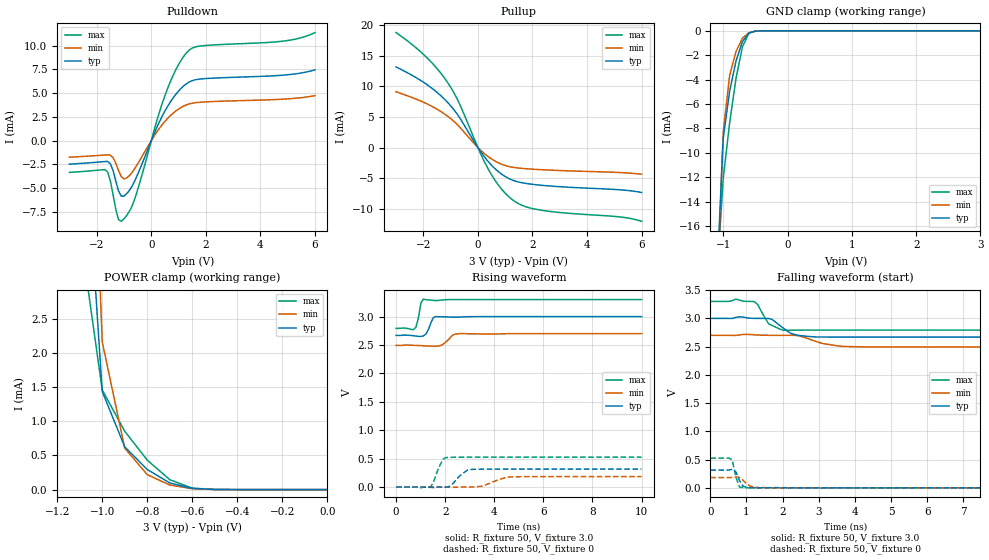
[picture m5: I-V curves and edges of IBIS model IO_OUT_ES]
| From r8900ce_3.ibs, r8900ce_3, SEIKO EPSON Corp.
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[Model]   IO_OUT_ES
Model_type 3-state
Enable Active-High
Polarity Non-Inverting
Vmeas=1.50
C_comp   2.5p   2p   3p
[Temperature Range] 25   85   -40
[Voltage Range]   3.0   2.7   3.3
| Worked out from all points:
|   slope of the pulldown table from 0 to 0.45 V, typ, clamps not added: 157 ohm
|   slope of the pullup table from 0 to 0.45 V, typ, clamps not added: 170 ohm
|   GND clamp passes 1 mA (typ) near -0.71 V on its own axis
|   POWER clamp passes 1 mA (typ) near -0.95 V on its own axis
|   falling waveform, R_fixture 50, V_fixture 3.0: 20-80 % time 430ps typ, 688ps min, 291ps max; typ from 3 V to 2.67 V
|   falling waveform, R_fixture 50, V_fixture 0: 20-80 % time 145ps typ, 215ps min, 125ps max; typ from 0.315 V to 0 V
|   rising waveform, R_fixture 50, V_fixture 3.0: 20-80 % time 196ps typ, 303ps min, 136ps max; typ from 2.67 V to 3 V
|   rising waveform, R_fixture 50, V_fixture 0: 20-80 % time 436ps typ, 664ps min, 290ps max; typ from 0 V to 0.315 V
[Pullup]
-3V       13.15mA    9.1mA      18.76mA
-2V       10.67mA    7.402mA    15.22mA
-1.2V     7.774mA    5.394mA    11.17mA
-700mV    5.069mA    3.488mA    7.383mA
100mV     -670.8uA   -442.9uA   -1.015mA
400mV     -2.405mA   -1.562mA   -3.683mA
800mV     -4.114mA   -2.598mA   -6.416mA
1.3V      -5.375mA   -3.246mA   -8.638mA
1.7V      -5.817mA   -3.436mA   -9.577mA
2.3V      -6.149mA   -3.611mA   -10.21mA
5.2V      -6.899mA   -4.083mA   -11.33mA
6V        -7.339mA   -4.363mA   -12.04mA
[Pulldown]
-3V       -2.479mA   -1.747mA   -3.344mA
-1.6V     -2.194mA   -1.497mA   -3.304mA
-1.4V     -3.175mA   -1.806mA   -5.728mA
-1.2V     -5.321mA   -3.18mA    -8.323mA
-1.1V     -5.852mA   -3.796mA   -8.495mA
-900mV    -5.578mA   -3.932mA   -7.863mA
-600mV    -4.197mA   -2.907mA   -6.073mA
600mV     3.627mA    2.353mA    5.517mA
1.3V      6.014mA    3.781mA    9.282mA
1.8V      6.487mA    4.045mA    9.961mA
4.8V      6.886mA    4.362mA    10.47mA
6V        7.452mA    4.738mA    11.38mA
[GND Clamp]
-3V       -430mA     -359.3mA   -539.8mA
-1.1V     -20.64mA   -22.12mA   -20.39mA
-1V       -8.831mA   -8.329mA   -12.11mA
-900mV    -4.941mA   -3.657mA   -7.543mA
-800mV    -2.459mA   -1.675mA   -3.865mA
-700mV    -864uA     -604.2uA   -1.29mA
-600mV    -179.4uA   -151uA     -195.7uA
-500mV    -26.95uA   -29.51uA   -18.23uA
-400mV    -3.685uA   -4.954uA   -1.653uA
3V        89.19pA    20.06nA    44.62pA
[POWER Clamp]
-3V       324.7mA    274.7mA    407.4mA
-1.1V     6.482mA    10.72mA    3.807mA
-1V       1.434mA    2.163mA    1.457mA
-900mV    625.6uA    606.7uA    853.6uA
-800mV    293.7uA    218.9uA    432uA
-700mV    98.19uA    66.89uA    145.6uA
-600mV    17.36uA    13.33uA    21.68uA
-500mV    1.719uA    1.888uA    1.298uA
0V        89.19pA    301.7pA    52.64pA
[Falling Waveform]
R_fixture=50
V_fixture=3.0
V_fixture_min=2.7
V_fixture_max=3.3
0s        3V         2.7V       3.3V
707.1ps   3.017V     2.698V     3.341V
1.212ns   3V         2.709V     3.297V
1.313ns   3V         2.705V     3.245V
1.616ns   2.998V     2.701V     2.902V
2.02ns    2.828V     2.7V       2.788V
2.424ns   2.702V     2.695V     2.791V
3.131ns   2.67V      2.553V     2.793V
3.737ns   2.668V     2.503V     2.793V
10ns      2.668V     2.493V     2.793V
[Falling Waveform]
R_fixture=50
V_fixture=0
V_fixture_min=0
V_fixture_max=0
0s        314.7mV    183mV      525mV
505.1ps   315.1mV    181.8mV    528.9mV
606.1ps   326.7mV    184.2mV    496.3mV
707.1ps   284.2mV    193.3mV    191.1mV
808.1ps   131.3mV    184.6mV    13.14mV
909.1ps   26.17mV    133.4mV    3.975mV
1.01ns    7.509mV    65.6mV     254.6uV
1.111ns   2.459mV    32.41mV    339.1uV
1.313ns   106.3uV    1.097mV    6.047mV
10ns      -2.85uV    6.225uV    4.767uV
[Rising Waveform]
R_fixture=50
V_fixture=3.0
V_fixture_min=2.7
V_fixture_max=3.3
0s        2.668V     2.493V     2.793V
808.1ps   2.658V     2.494V     2.811V
909.1ps   2.653V     2.492V     2.974V
1.01ns    2.65V      2.489V     3.236V
1.111ns   2.659V     2.487V     3.308V
1.313ns   2.767V     2.482V     3.296V
1.515ns   2.98V      2.479V     3.286V
1.616ns   3.001V     2.479V     3.282V
2.626ns   2.993V     2.701V     3.3V
10ns      3V         2.7V       3.3V
[Rising Waveform]
R_fixture=50
V_fixture=0
V_fixture_min=0
V_fixture_max=0
0s        0V         0V         0V
1.414ns   -7.076mV   137.7uV    9.127mV
1.818ns   -1.446mV   -520.9uV   410.3mV
2.02ns    -2.504mV   -2.263mV   516.2mV
2.222ns   22.91mV    -4.717mV   522.2mV
2.626ns   206.6mV    296.6uV    524.2mV
3.03ns    308.6mV    -1.038mV   524.8mV
3.535ns   314mV      17.63mV    525mV
4.646ns   314.7mV    177.5mV    525mV
10ns      314.7mV    183mV      525mV
[Ramp]
R_load=50
dV/dt_r   1.888E-1/4.356E-10   1.098E-1/6.639E-10   3.150E-1/2.883E-10
dV/dt_f   1.989E-1/4.288E-10   1.243E-1/6.875E-10   3.044E-1/2.913E-10
|[End   IO_OUT_ES
